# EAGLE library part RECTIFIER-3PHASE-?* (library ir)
THREE PHASE BRIDGE Source: http://www.irf.com/product-info/datasheets/data/36mt.pdf

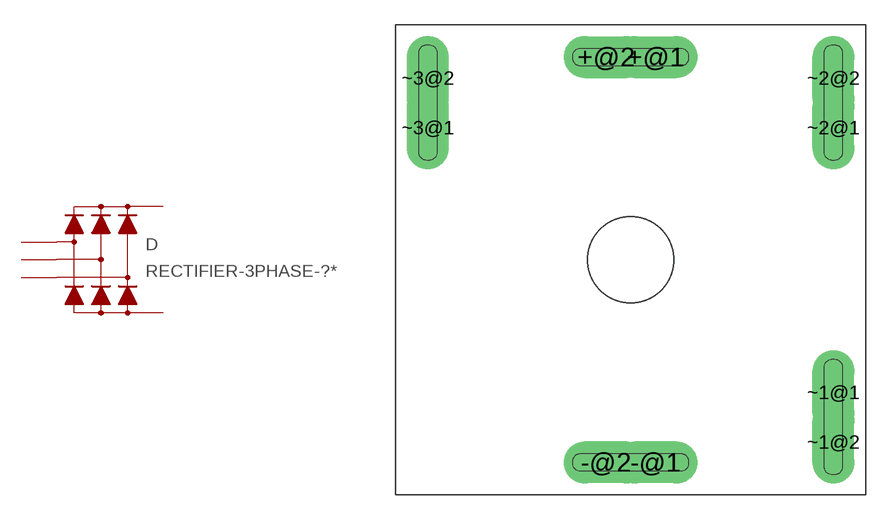
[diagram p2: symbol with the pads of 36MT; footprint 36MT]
Designator prefix D

## RECTIFIER-3PHASE-36MT10 (MF: INTERNATIONAL RECTIFIER(IR); MPN: VS-36MT10; OC_FARNELL: unknown; OC_NEWARK: 09F6869), RECTIFIER-3PHASE-36MT100 (MF: INTERNATIONAL RECTIFIER(IR); MPN: VS-36MT100; OC_FARNELL: 2422293; OC_NEWARK: 09F6870), RECTIFIER-3PHASE-36MT120 (MF: INTERNATIONAL RECTIFIER(IR); MPN: 36MT120; OC_FARNELL: 9098917; OC_NEWARK: 09F6871), RECTIFIER-3PHASE-36MT140 (MF: INTERNATIONAL RECTIFIER(IR); MPN: 36MT140; OC_FARNELL: 9098895; OC_NEWARK: 48F1237), RECTIFIER-3PHASE-36MT160 (MF: INTERNATIONAL RECTIFIER(IR); MPN: VS-36MT160; OC_FARNELL: 9098879; OC_NEWARK: 48F1238), RECTIFIER-3PHASE-36MT20 (MF: INTERNATIONAL RECTIFIER(IR); MPN: 36MT20; OC_FARNELL: 2422311; OC_NEWARK: 09F6872), RECTIFIER-3PHASE-36MT40 (MPN: 36MT40PBF; OC_FARNELL: 9098860; OC_NEWARK: 98K8885), RECTIFIER-3PHASE-36MT5 (OC_FARNELL: unknown; OC_NEWARK: unknown), RECTIFIER-3PHASE-36MT60 (MF: INTERNATIONAL RECTIFIER(IR); MPN: 36MT60; OC_FARNELL: 2422335; OC_NEWARK: 09F6874), RECTIFIER-3PHASE-36MT80 (MF: INTERNATIONAL RECTIFIER(IR); MPN: VS-36MT80; OC_FARNELL: 9098887; OC_NEWARK: 09F6875)  [36MT]
+@1  +  pas
+@2  +  pas
-@1  -  pas
-@2  -  pas
~1@1  ~1  pas
~1@2  ~1  pas
~2@1  ~2  pas
~2@2  ~2  pas
~3@1  ~3  pas
~3@2  ~3  pas

## Footprint 36MT (pad centres in mm)
Source: http://www.irf.com/product-info/datasheets/data/36mt.pdf
drill 1.1 pad 2.54 long: +@1 1.5,12.25; +@2 -1.5,12.25; -@1 1.5,-12.25; -@2 -1.5,-12.25; ~1@1 12.25,-8; ~1@2 12.25,-11; ~2@1 12.25,8; ~2@2 12.25,11; ~3@1 -12.25,8; ~3@2 -12.25,11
